VERSION 5.7 ;
  NOWIREEXTENSIONATPIN ON ;
  DIVIDERCHAR "/" ;
  BUSBITCHARS "[]" ;
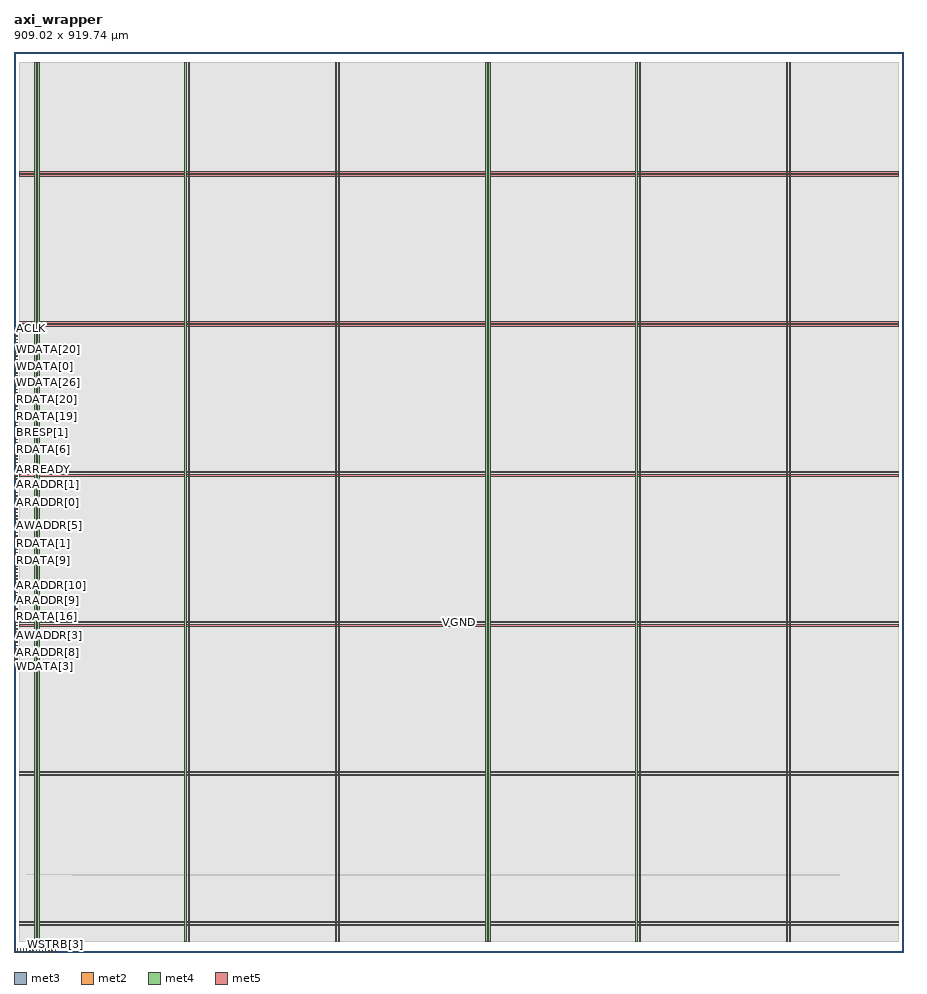
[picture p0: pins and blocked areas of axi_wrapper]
MACRO axi_wrapper
  CLASS BLOCK ;
  FOREIGN axi_wrapper ;
  ORIGIN 0.000 0.000 ;
  SIZE 909.020 BY 919.740 ;
  PIN ACLK
    DIRECTION INPUT ;
    USE SIGNAL ;
    PORT
      LAYER met3 ;
        RECT 0.000 629.040 4.000 629.640 ;
    END
  END ACLK
  PIN ARADDR[0]
    DIRECTION INPUT ;
    USE SIGNAL ;
    PORT
      LAYER met3 ;
        RECT 0.000 459.040 4.000 459.640 ;
    END
  END ARADDR[0]
  PIN ARADDR[10]
    DIRECTION INPUT ;
    USE SIGNAL ;
    PORT
      LAYER met3 ;
        RECT 0.000 374.040 4.000 374.640 ;
    END
  END ARADDR[10]
  PIN ARADDR[11]
    DIRECTION INPUT ;
    USE SIGNAL ;
    PORT
      LAYER met3 ;
        RECT 0.000 465.840 4.000 466.440 ;
    END
  END ARADDR[11]
  PIN ARADDR[1]
    DIRECTION INPUT ;
    USE SIGNAL ;
    PORT
      LAYER met3 ;
        RECT 0.000 469.240 4.000 469.840 ;
    END
  END ARADDR[1]
  PIN ARADDR[2]
    DIRECTION INPUT ;
    USE SIGNAL ;
    PORT
      LAYER met3 ;
        RECT 0.000 455.640 4.000 456.240 ;
    END
  END ARADDR[2]
  PIN ARADDR[3]
    DIRECTION INPUT ;
    USE SIGNAL ;
    PORT
      LAYER met3 ;
        RECT 0.000 472.640 4.000 473.240 ;
    END
  END ARADDR[3]
  PIN ARADDR[4]
    DIRECTION INPUT ;
    USE SIGNAL ;
    PORT
      LAYER met3 ;
        RECT 0.000 326.440 4.000 327.040 ;
    END
  END ARADDR[4]
  PIN ARADDR[5]
    DIRECTION INPUT ;
    USE SIGNAL ;
    PORT
      LAYER met3 ;
        RECT 0.000 479.440 4.000 480.040 ;
    END
  END ARADDR[5]
  PIN ARADDR[6]
    DIRECTION INPUT ;
    USE SIGNAL ;
    PORT
      LAYER met3 ;
        RECT 0.000 428.440 4.000 429.040 ;
    END
  END ARADDR[6]
  PIN ARADDR[7]
    DIRECTION INPUT ;
    USE SIGNAL ;
    PORT
      LAYER met3 ;
        RECT 0.000 482.840 4.000 483.440 ;
    END
  END ARADDR[7]
  PIN ARADDR[8]
    DIRECTION INPUT ;
    USE SIGNAL ;
    PORT
      LAYER met3 ;
        RECT 0.000 306.040 4.000 306.640 ;
    END
  END ARADDR[8]
  PIN ARADDR[9]
    DIRECTION INPUT ;
    USE SIGNAL ;
    PORT
      LAYER met3 ;
        RECT 0.000 367.240 4.000 367.840 ;
    END
  END ARADDR[9]
  PIN ARESETn
    DIRECTION INPUT ;
    USE SIGNAL ;
    PORT
      LAYER met3 ;
        RECT 0.000 411.440 4.000 412.040 ;
    END
  END ARESETn
  PIN ARPROT[0]
    DIRECTION INPUT ;
    USE SIGNAL ;
    PORT
      LAYER met2 ;
        RECT 0.090 0.000 0.370 4.000 ;
    END
  END ARPROT[0]
  PIN ARPROT[1]
    DIRECTION INPUT ;
    USE SIGNAL ;
    PORT
      LAYER met2 ;
        RECT 3.310 0.000 3.590 4.000 ;
    END
  END ARPROT[1]
  PIN ARPROT[2]
    DIRECTION INPUT ;
    USE SIGNAL ;
    PORT
      LAYER met2 ;
        RECT 6.530 0.000 6.810 4.000 ;
    END
  END ARPROT[2]
  PIN ARREADY
    DIRECTION OUTPUT TRISTATE ;
    USE SIGNAL ;
    PORT
      LAYER met3 ;
        RECT 0.000 493.040 4.000 493.640 ;
    END
  END ARREADY
  PIN ARVALID
    DIRECTION INPUT ;
    USE SIGNAL ;
    PORT
      LAYER met3 ;
        RECT 0.000 496.440 4.000 497.040 ;
    END
  END ARVALID
  PIN AWADDR[0]
    DIRECTION INPUT ;
    USE SIGNAL ;
    PORT
      LAYER met3 ;
        RECT 0.000 499.840 4.000 500.440 ;
    END
  END AWADDR[0]
  PIN AWADDR[10]
    DIRECTION INPUT ;
    USE SIGNAL ;
    PORT
      LAYER met2 ;
        RECT 9.750 0.000 10.030 4.000 ;
    END
  END AWADDR[10]
  PIN AWADDR[11]
    DIRECTION INPUT ;
    USE SIGNAL ;
    PORT
      LAYER met2 ;
        RECT 12.970 0.000 13.250 4.000 ;
    END
  END AWADDR[11]
  PIN AWADDR[1]
    DIRECTION INPUT ;
    USE SIGNAL ;
    PORT
      LAYER met3 ;
        RECT 0.000 292.440 4.000 293.040 ;
    END
  END AWADDR[1]
  PIN AWADDR[2]
    DIRECTION INPUT ;
    USE SIGNAL ;
    PORT
      LAYER met3 ;
        RECT 0.000 503.240 4.000 503.840 ;
    END
  END AWADDR[2]
  PIN AWADDR[3]
    DIRECTION INPUT ;
    USE SIGNAL ;
    PORT
      LAYER met3 ;
        RECT 0.000 323.040 4.000 323.640 ;
    END
  END AWADDR[3]
  PIN AWADDR[4]
    DIRECTION INPUT ;
    USE SIGNAL ;
    PORT
      LAYER met3 ;
        RECT 0.000 510.040 4.000 510.640 ;
    END
  END AWADDR[4]
  PIN AWADDR[5]
    DIRECTION INPUT ;
    USE SIGNAL ;
    PORT
      LAYER met3 ;
        RECT 0.000 435.240 4.000 435.840 ;
    END
  END AWADDR[5]
  PIN AWADDR[6]
    DIRECTION INPUT ;
    USE SIGNAL ;
    PORT
      LAYER met3 ;
        RECT 0.000 360.440 4.000 361.040 ;
    END
  END AWADDR[6]
  PIN AWADDR[7]
    DIRECTION INPUT ;
    USE SIGNAL ;
    PORT
      LAYER met3 ;
        RECT 0.000 516.840 4.000 517.440 ;
    END
  END AWADDR[7]
  PIN AWADDR[8]
    DIRECTION INPUT ;
    USE SIGNAL ;
    PORT
      LAYER met2 ;
        RECT 16.190 0.000 16.470 4.000 ;
    END
  END AWADDR[8]
  PIN AWADDR[9]
    DIRECTION INPUT ;
    USE SIGNAL ;
    PORT
      LAYER met2 ;
        RECT 19.410 0.000 19.690 4.000 ;
    END
  END AWADDR[9]
  PIN AWPROT[0]
    DIRECTION INPUT ;
    USE SIGNAL ;
    PORT
      LAYER met2 ;
        RECT 22.630 0.000 22.910 4.000 ;
    END
  END AWPROT[0]
  PIN AWPROT[1]
    DIRECTION INPUT ;
    USE SIGNAL ;
    PORT
      LAYER met2 ;
        RECT 25.850 0.000 26.130 4.000 ;
    END
  END AWPROT[1]
  PIN AWPROT[2]
    DIRECTION INPUT ;
    USE SIGNAL ;
    PORT
      LAYER met2 ;
        RECT 29.070 0.000 29.350 4.000 ;
    END
  END AWPROT[2]
  PIN AWREADY
    DIRECTION OUTPUT TRISTATE ;
    USE SIGNAL ;
    PORT
      LAYER met3 ;
        RECT 0.000 506.640 4.000 507.240 ;
    END
  END AWREADY
  PIN AWVALID
    DIRECTION INPUT ;
    USE SIGNAL ;
    PORT
      LAYER met3 ;
        RECT 0.000 438.640 4.000 439.240 ;
    END
  END AWVALID
  PIN BREADY
    DIRECTION INPUT ;
    USE SIGNAL ;
    PORT
      LAYER met3 ;
        RECT 0.000 523.640 4.000 524.240 ;
    END
  END BREADY
  PIN BRESP[0]
    DIRECTION OUTPUT TRISTATE ;
    USE SIGNAL ;
    PORT
      LAYER met3 ;
        RECT 0.000 357.040 4.000 357.640 ;
    END
  END BRESP[0]
  PIN BRESP[1]
    DIRECTION OUTPUT TRISTATE ;
    USE SIGNAL ;
    PORT
      LAYER met3 ;
        RECT 0.000 530.440 4.000 531.040 ;
    END
  END BRESP[1]
  PIN BVALID
    DIRECTION OUTPUT TRISTATE ;
    USE SIGNAL ;
    PORT
      LAYER met3 ;
        RECT 0.000 319.640 4.000 320.240 ;
    END
  END BVALID
  PIN RDATA[0]
    DIRECTION OUTPUT TRISTATE ;
    USE SIGNAL ;
    PORT
      LAYER met3 ;
        RECT 0.000 533.840 4.000 534.440 ;
    END
  END RDATA[0]
  PIN RDATA[10]
    DIRECTION OUTPUT TRISTATE ;
    USE SIGNAL ;
    PORT
      LAYER met3 ;
        RECT 0.000 537.240 4.000 537.840 ;
    END
  END RDATA[10]
  PIN RDATA[11]
    DIRECTION OUTPUT TRISTATE ;
    USE SIGNAL ;
    PORT
      LAYER met3 ;
        RECT 0.000 353.640 4.000 354.240 ;
    END
  END RDATA[11]
  PIN RDATA[12]
    DIRECTION OUTPUT TRISTATE ;
    USE SIGNAL ;
    PORT
      LAYER met3 ;
        RECT 0.000 431.840 4.000 432.440 ;
    END
  END RDATA[12]
  PIN RDATA[13]
    DIRECTION OUTPUT TRISTATE ;
    USE SIGNAL ;
    PORT
      LAYER met3 ;
        RECT 0.000 544.040 4.000 544.640 ;
    END
  END RDATA[13]
  PIN RDATA[14]
    DIRECTION OUTPUT TRISTATE ;
    USE SIGNAL ;
    PORT
      LAYER met3 ;
        RECT 0.000 346.840 4.000 347.440 ;
    END
  END RDATA[14]
  PIN RDATA[15]
    DIRECTION OUTPUT TRISTATE ;
    USE SIGNAL ;
    PORT
      LAYER met3 ;
        RECT 0.000 550.840 4.000 551.440 ;
    END
  END RDATA[15]
  PIN RDATA[16]
    DIRECTION OUTPUT TRISTATE ;
    USE SIGNAL ;
    PORT
      LAYER met3 ;
        RECT 0.000 350.240 4.000 350.840 ;
    END
  END RDATA[16]
  PIN RDATA[17]
    DIRECTION OUTPUT TRISTATE ;
    USE SIGNAL ;
    PORT
      LAYER met3 ;
        RECT 0.000 486.240 4.000 486.840 ;
    END
  END RDATA[17]
  PIN RDATA[18]
    DIRECTION OUTPUT TRISTATE ;
    USE SIGNAL ;
    PORT
      LAYER met3 ;
        RECT 0.000 421.640 4.000 422.240 ;
    END
  END RDATA[18]
  PIN RDATA[19]
    DIRECTION OUTPUT TRISTATE ;
    USE SIGNAL ;
    PORT
      LAYER met3 ;
        RECT 0.000 547.440 4.000 548.040 ;
    END
  END RDATA[19]
  PIN RDATA[1]
    DIRECTION OUTPUT TRISTATE ;
    USE SIGNAL ;
    PORT
      LAYER met3 ;
        RECT 0.000 425.040 4.000 425.640 ;
    END
  END RDATA[1]
  PIN RDATA[20]
    DIRECTION OUTPUT TRISTATE ;
    USE SIGNAL ;
    PORT
      LAYER met3 ;
        RECT 0.000 564.440 4.000 565.040 ;
    END
  END RDATA[20]
  PIN RDATA[21]
    DIRECTION OUTPUT TRISTATE ;
    USE SIGNAL ;
    PORT
      LAYER met3 ;
        RECT 0.000 302.640 4.000 303.240 ;
    END
  END RDATA[21]
  PIN RDATA[22]
    DIRECTION OUTPUT TRISTATE ;
    USE SIGNAL ;
    PORT
      LAYER met3 ;
        RECT 0.000 316.240 4.000 316.840 ;
    END
  END RDATA[22]
  PIN RDATA[23]
    DIRECTION OUTPUT TRISTATE ;
    USE SIGNAL ;
    PORT
      LAYER met3 ;
        RECT 0.000 404.640 4.000 405.240 ;
    END
  END RDATA[23]
  PIN RDATA[24]
    DIRECTION OUTPUT TRISTATE ;
    USE SIGNAL ;
    PORT
      LAYER met3 ;
        RECT 0.000 571.240 4.000 571.840 ;
    END
  END RDATA[24]
  PIN RDATA[25]
    DIRECTION OUTPUT TRISTATE ;
    USE SIGNAL ;
    PORT
      LAYER met3 ;
        RECT 0.000 445.440 4.000 446.040 ;
    END
  END RDATA[25]
  PIN RDATA[26]
    DIRECTION OUTPUT TRISTATE ;
    USE SIGNAL ;
    PORT
      LAYER met3 ;
        RECT 0.000 574.640 4.000 575.240 ;
    END
  END RDATA[26]
  PIN RDATA[27]
    DIRECTION OUTPUT TRISTATE ;
    USE SIGNAL ;
    PORT
      LAYER met3 ;
        RECT 0.000 418.240 4.000 418.840 ;
    END
  END RDATA[27]
  PIN RDATA[28]
    DIRECTION OUTPUT TRISTATE ;
    USE SIGNAL ;
    PORT
      LAYER met3 ;
        RECT 0.000 561.040 4.000 561.640 ;
    END
  END RDATA[28]
  PIN RDATA[29]
    DIRECTION OUTPUT TRISTATE ;
    USE SIGNAL ;
    PORT
      LAYER met3 ;
        RECT 0.000 584.840 4.000 585.440 ;
    END
  END RDATA[29]
  PIN RDATA[2]
    DIRECTION OUTPUT TRISTATE ;
    USE SIGNAL ;
    PORT
      LAYER met3 ;
        RECT 0.000 540.640 4.000 541.240 ;
    END
  END RDATA[2]
  PIN RDATA[30]
    DIRECTION OUTPUT TRISTATE ;
    USE SIGNAL ;
    PORT
      LAYER met3 ;
        RECT 0.000 343.440 4.000 344.040 ;
    END
  END RDATA[30]
  PIN RDATA[31]
    DIRECTION OUTPUT TRISTATE ;
    USE SIGNAL ;
    PORT
      LAYER met3 ;
        RECT 0.000 588.240 4.000 588.840 ;
    END
  END RDATA[31]
  PIN RDATA[3]
    DIRECTION OUTPUT TRISTATE ;
    USE SIGNAL ;
    PORT
      LAYER met3 ;
        RECT 0.000 527.040 4.000 527.640 ;
    END
  END RDATA[3]
  PIN RDATA[4]
    DIRECTION OUTPUT TRISTATE ;
    USE SIGNAL ;
    PORT
      LAYER met3 ;
        RECT 0.000 591.640 4.000 592.240 ;
    END
  END RDATA[4]
  PIN RDATA[5]
    DIRECTION OUTPUT TRISTATE ;
    USE SIGNAL ;
    PORT
      LAYER met3 ;
        RECT 0.000 295.840 4.000 296.440 ;
    END
  END RDATA[5]
  PIN RDATA[6]
    DIRECTION OUTPUT TRISTATE ;
    USE SIGNAL ;
    PORT
      LAYER met3 ;
        RECT 0.000 513.440 4.000 514.040 ;
    END
  END RDATA[6]
  PIN RDATA[7]
    DIRECTION OUTPUT TRISTATE ;
    USE SIGNAL ;
    PORT
      LAYER met3 ;
        RECT 0.000 595.040 4.000 595.640 ;
    END
  END RDATA[7]
  PIN RDATA[8]
    DIRECTION OUTPUT TRISTATE ;
    USE SIGNAL ;
    PORT
      LAYER met3 ;
        RECT 0.000 312.840 4.000 313.440 ;
    END
  END RDATA[8]
  PIN RDATA[9]
    DIRECTION OUTPUT TRISTATE ;
    USE SIGNAL ;
    PORT
      LAYER met3 ;
        RECT 0.000 408.040 4.000 408.640 ;
    END
  END RDATA[9]
  PIN RREADY
    DIRECTION INPUT ;
    USE SIGNAL ;
    PORT
      LAYER met3 ;
        RECT 0.000 489.640 4.000 490.240 ;
    END
  END RREADY
  PIN RRESP[0]
    DIRECTION OUTPUT TRISTATE ;
    USE SIGNAL ;
    PORT
      LAYER met3 ;
        RECT 0.000 557.640 4.000 558.240 ;
    END
  END RRESP[0]
  PIN RRESP[1]
    DIRECTION OUTPUT TRISTATE ;
    USE SIGNAL ;
    PORT
      LAYER met3 ;
        RECT 0.000 476.040 4.000 476.640 ;
    END
  END RRESP[1]
  PIN RVALID
    DIRECTION OUTPUT TRISTATE ;
    USE SIGNAL ;
    PORT
      LAYER met3 ;
        RECT 0.000 340.040 4.000 340.640 ;
    END
  END RVALID
  PIN VGND
    DIRECTION INOUT ;
    USE GROUND ;
    PORT
      LAYER met4 ;
        RECT 24.340 10.640 25.940 908.720 ;
    END
    PORT
      LAYER met4 ;
        RECT 177.940 10.640 179.540 908.720 ;
    END
    PORT
      LAYER met4 ;
        RECT 331.540 10.640 333.140 908.720 ;
    END
    PORT
      LAYER met4 ;
        RECT 485.140 10.640 486.740 908.720 ;
    END
    PORT
      LAYER met4 ;
        RECT 638.740 10.640 640.340 908.720 ;
    END
    PORT
      LAYER met4 ;
        RECT 792.340 10.640 793.940 908.720 ;
    END
    PORT
      LAYER met5 ;
        RECT 5.280 30.030 903.680 31.630 ;
    END
    PORT
      LAYER met5 ;
        RECT 5.280 183.210 903.680 184.810 ;
    END
    PORT
      LAYER met5 ;
        RECT 5.280 336.390 903.680 337.990 ;
    END
    PORT
      LAYER met5 ;
        RECT 5.280 489.570 903.680 491.170 ;
    END
    PORT
      LAYER met5 ;
        RECT 5.280 642.750 903.680 644.350 ;
    END
    PORT
      LAYER met5 ;
        RECT 5.280 795.930 903.680 797.530 ;
    END
  END VGND
  PIN VPWR
    DIRECTION INOUT ;
    USE POWER ;
    PORT
      LAYER met4 ;
        RECT 21.040 10.640 22.640 908.720 ;
    END
    PORT
      LAYER met4 ;
        RECT 174.640 10.640 176.240 908.720 ;
    END
    PORT
      LAYER met4 ;
        RECT 328.240 10.640 329.840 908.720 ;
    END
    PORT
      LAYER met4 ;
        RECT 481.840 10.640 483.440 908.720 ;
    END
    PORT
      LAYER met4 ;
        RECT 635.440 10.640 637.040 908.720 ;
    END
    PORT
      LAYER met4 ;
        RECT 789.040 10.640 790.640 908.720 ;
    END
    PORT
      LAYER met5 ;
        RECT 5.280 26.730 903.680 28.330 ;
    END
    PORT
      LAYER met5 ;
        RECT 5.280 179.910 903.680 181.510 ;
    END
    PORT
      LAYER met5 ;
        RECT 5.280 333.090 903.680 334.690 ;
    END
    PORT
      LAYER met5 ;
        RECT 5.280 486.270 903.680 487.870 ;
    END
    PORT
      LAYER met5 ;
        RECT 5.280 639.450 903.680 641.050 ;
    END
    PORT
      LAYER met5 ;
        RECT 5.280 792.630 903.680 794.230 ;
    END
  END VPWR
  PIN WDATA[0]
    DIRECTION INPUT ;
    USE SIGNAL ;
    PORT
      LAYER met3 ;
        RECT 0.000 598.440 4.000 599.040 ;
    END
  END WDATA[0]
  PIN WDATA[10]
    DIRECTION INPUT ;
    USE SIGNAL ;
    PORT
      LAYER met3 ;
        RECT 0.000 462.440 4.000 463.040 ;
    END
  END WDATA[10]
  PIN WDATA[11]
    DIRECTION INPUT ;
    USE SIGNAL ;
    PORT
      LAYER met3 ;
        RECT 0.000 601.840 4.000 602.440 ;
    END
  END WDATA[11]
  PIN WDATA[12]
    DIRECTION INPUT ;
    USE SIGNAL ;
    PORT
      LAYER met3 ;
        RECT 0.000 401.240 4.000 401.840 ;
    END
  END WDATA[12]
  PIN WDATA[13]
    DIRECTION INPUT ;
    USE SIGNAL ;
    PORT
      LAYER met3 ;
        RECT 0.000 442.040 4.000 442.640 ;
    END
  END WDATA[13]
  PIN WDATA[14]
    DIRECTION INPUT ;
    USE SIGNAL ;
    PORT
      LAYER met3 ;
        RECT 0.000 605.240 4.000 605.840 ;
    END
  END WDATA[14]
  PIN WDATA[15]
    DIRECTION INPUT ;
    USE SIGNAL ;
    PORT
      LAYER met3 ;
        RECT 0.000 608.640 4.000 609.240 ;
    END
  END WDATA[15]
  PIN WDATA[16]
    DIRECTION INPUT ;
    USE SIGNAL ;
    PORT
      LAYER met3 ;
        RECT 0.000 397.840 4.000 398.440 ;
    END
  END WDATA[16]
  PIN WDATA[17]
    DIRECTION INPUT ;
    USE SIGNAL ;
    PORT
      LAYER met3 ;
        RECT 0.000 554.240 4.000 554.840 ;
    END
  END WDATA[17]
  PIN WDATA[18]
    DIRECTION INPUT ;
    USE SIGNAL ;
    PORT
      LAYER met3 ;
        RECT 0.000 612.040 4.000 612.640 ;
    END
  END WDATA[18]
  PIN WDATA[19]
    DIRECTION INPUT ;
    USE SIGNAL ;
    PORT
      LAYER met3 ;
        RECT 0.000 336.640 4.000 337.240 ;
    END
  END WDATA[19]
  PIN WDATA[1]
    DIRECTION INPUT ;
    USE SIGNAL ;
    PORT
      LAYER met3 ;
        RECT 0.000 394.440 4.000 395.040 ;
    END
  END WDATA[1]
  PIN WDATA[20]
    DIRECTION INPUT ;
    USE SIGNAL ;
    PORT
      LAYER met3 ;
        RECT 0.000 615.440 4.000 616.040 ;
    END
  END WDATA[20]
  PIN WDATA[21]
    DIRECTION INPUT ;
    USE SIGNAL ;
    PORT
      LAYER met3 ;
        RECT 0.000 567.840 4.000 568.440 ;
    END
  END WDATA[21]
  PIN WDATA[22]
    DIRECTION INPUT ;
    USE SIGNAL ;
    PORT
      LAYER met3 ;
        RECT 0.000 618.840 4.000 619.440 ;
    END
  END WDATA[22]
  PIN WDATA[23]
    DIRECTION INPUT ;
    USE SIGNAL ;
    PORT
      LAYER met3 ;
        RECT 0.000 391.040 4.000 391.640 ;
    END
  END WDATA[23]
  PIN WDATA[24]
    DIRECTION INPUT ;
    USE SIGNAL ;
    PORT
      LAYER met3 ;
        RECT 0.000 622.240 4.000 622.840 ;
    END
  END WDATA[24]
  PIN WDATA[25]
    DIRECTION INPUT ;
    USE SIGNAL ;
    PORT
      LAYER met3 ;
        RECT 0.000 387.640 4.000 388.240 ;
    END
  END WDATA[25]
  PIN WDATA[26]
    DIRECTION INPUT ;
    USE SIGNAL ;
    PORT
      LAYER met3 ;
        RECT 0.000 581.440 4.000 582.040 ;
    END
  END WDATA[26]
  PIN WDATA[27]
    DIRECTION INPUT ;
    USE SIGNAL ;
    PORT
      LAYER met3 ;
        RECT 0.000 380.840 4.000 381.440 ;
    END
  END WDATA[27]
  PIN WDATA[28]
    DIRECTION INPUT ;
    USE SIGNAL ;
    PORT
      LAYER met3 ;
        RECT 0.000 333.240 4.000 333.840 ;
    END
  END WDATA[28]
  PIN WDATA[29]
    DIRECTION INPUT ;
    USE SIGNAL ;
    PORT
      LAYER met3 ;
        RECT 0.000 309.440 4.000 310.040 ;
    END
  END WDATA[29]
  PIN WDATA[2]
    DIRECTION INPUT ;
    USE SIGNAL ;
    PORT
      LAYER met3 ;
        RECT 0.000 520.240 4.000 520.840 ;
    END
  END WDATA[2]
  PIN WDATA[30]
    DIRECTION INPUT ;
    USE SIGNAL ;
    PORT
      LAYER met3 ;
        RECT 0.000 384.240 4.000 384.840 ;
    END
  END WDATA[30]
  PIN WDATA[31]
    DIRECTION INPUT ;
    USE SIGNAL ;
    PORT
      LAYER met3 ;
        RECT 0.000 625.640 4.000 626.240 ;
    END
  END WDATA[31]
  PIN WDATA[3]
    DIRECTION INPUT ;
    USE SIGNAL ;
    PORT
      LAYER met3 ;
        RECT 0.000 299.240 4.000 299.840 ;
    END
  END WDATA[3]
  PIN WDATA[4]
    DIRECTION INPUT ;
    USE SIGNAL ;
    PORT
      LAYER met3 ;
        RECT 0.000 370.640 4.000 371.240 ;
    END
  END WDATA[4]
  PIN WDATA[5]
    DIRECTION INPUT ;
    USE SIGNAL ;
    PORT
      LAYER met3 ;
        RECT 0.000 363.840 4.000 364.440 ;
    END
  END WDATA[5]
  PIN WDATA[6]
    DIRECTION INPUT ;
    USE SIGNAL ;
    PORT
      LAYER met3 ;
        RECT 0.000 414.840 4.000 415.440 ;
    END
  END WDATA[6]
  PIN WDATA[7]
    DIRECTION INPUT ;
    USE SIGNAL ;
    PORT
      LAYER met3 ;
        RECT 0.000 448.840 4.000 449.440 ;
    END
  END WDATA[7]
  PIN WDATA[8]
    DIRECTION INPUT ;
    USE SIGNAL ;
    PORT
      LAYER met3 ;
        RECT 0.000 329.840 4.000 330.440 ;
    END
  END WDATA[8]
  PIN WDATA[9]
    DIRECTION INPUT ;
    USE SIGNAL ;
    PORT
      LAYER met3 ;
        RECT 0.000 377.440 4.000 378.040 ;
    END
  END WDATA[9]
  PIN WREADY
    DIRECTION OUTPUT TRISTATE ;
    USE SIGNAL ;
    PORT
      LAYER met3 ;
        RECT 0.000 578.040 4.000 578.640 ;
    END
  END WREADY
  PIN WSTRB[0]
    DIRECTION INPUT ;
    USE SIGNAL ;
    PORT
      LAYER met2 ;
        RECT 32.290 0.000 32.570 4.000 ;
    END
  END WSTRB[0]
  PIN WSTRB[1]
    DIRECTION INPUT ;
    USE SIGNAL ;
    PORT
      LAYER met2 ;
        RECT 35.510 0.000 35.790 4.000 ;
    END
  END WSTRB[1]
  PIN WSTRB[2]
    DIRECTION INPUT ;
    USE SIGNAL ;
    PORT
      LAYER met2 ;
        RECT 38.730 0.000 39.010 4.000 ;
    END
  END WSTRB[2]
  PIN WSTRB[3]
    DIRECTION INPUT ;
    USE SIGNAL ;
    PORT
      LAYER met2 ;
        RECT 41.950 0.000 42.230 4.000 ;
    END
  END WSTRB[3]
  PIN WVALID
    DIRECTION INPUT ;
    USE SIGNAL ;
    PORT
      LAYER met3 ;
        RECT 0.000 452.240 4.000 452.840 ;
    END
  END WVALID
  OBS
      LAYER li1 ;
        RECT 5.520 10.795 903.440 908.565 ;
      LAYER met1 ;
        RECT 5.520 10.640 903.440 908.720 ;
      LAYER met2 ;
        RECT 111.020 78.600 386.470 78.940 ;
      LAYER met3 ;
        RECT 12.950 78.765 841.570 79.065 ;
      LAYER met4 ;
        RECT 60.110 78.295 174.240 79.535 ;
        RECT 176.640 78.295 177.540 79.535 ;
        RECT 179.940 78.295 327.840 79.535 ;
        RECT 330.240 78.295 331.140 79.535 ;
        RECT 333.540 78.295 481.440 79.535 ;
        RECT 483.840 78.295 484.740 79.535 ;
        RECT 487.140 78.295 635.040 79.535 ;
        RECT 637.440 78.295 638.340 79.535 ;
        RECT 640.740 78.295 788.640 79.535 ;
        RECT 791.040 78.295 791.940 79.535 ;
        RECT 794.340 78.295 843.560 79.535 ;
  END
END axi_wrapper
END LIBRARY

